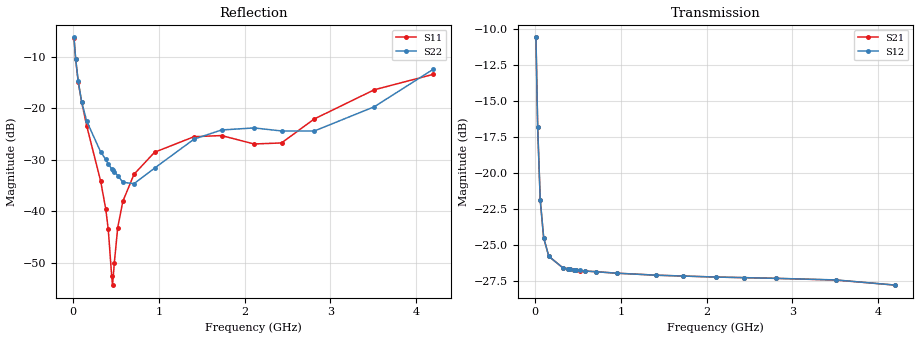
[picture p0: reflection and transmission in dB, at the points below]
! Integrated Device Technology
! Corporate Headquarters
! 6024 Silver Creek Valley Road
! San Jose, CA 95138  USA
! Phone:  1-408-284-8200
! Toll Free:  1-800-223-1366
! Webpage:  http://www.idt.com/
! Timing and RF Division
! 515 Groton Road, Suite 102
! Westford, MA 01886-6024
! Device:  F1950
! Description: 7-bit 0.25 dB Digital Step Attenuator
! Frequency:  150.0 -  4000.00 MHz
! Package:  4x4 mm Thin QFN Plastic Package: 24 pin
! Ports:  2 RF, 12 DC
!  Pin  1  = D0
!  Pin  2  = VDD
!  Pin  3  = Vmode
!  Pin  4  = GND
!  Pin  5  = RF1  =  Port 1
!  Pin  6  = GND
!  Pin  7  = GND
!  Pin  8  = GND
!  Pin  9  = GND
!  Pin 10  = GND
!  Pin 11  = GND
!  Pin 12  = GND
!  Pin 13  = GND
!  Pin 14  = RF2  =  Port 2
!  Pin 15  = GND
!  Pin 16  = LE
!  Pin 17  = CLK
!  Pin 18  = DATE
!  Pin 19  = D6
!  Pin 20  = D5
!  Pin 21  = D4
!  Pin 22  = D3
!  Pin 23  = D2
!  Pin 24  = D1
! State:  104
! Atten State:  26.00 dB
! Voltage:  +5.00 Volts
! Current:  Not Measured mA
! Data:  The device was measured on a the F195X evaluation board which has
!  individual transmission lines to the RF pins.  Data was collected
!  using a calibrated network analyzer.  The evaluation board was
!  de-embedded using a TRL calibration technique.
!  The reference plane is the edge of the package pin.
! Misc:  Board 2019
!  Action Tracker AT0250
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# GHz S dB R 50
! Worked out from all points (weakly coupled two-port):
!   420 points, 10 MHz to 4.2 GHz, reference 50 ohm
!   highest |S21| = -10.60 dB at 10 MHz (marker M1); lowest = -27.8 dB at 4.2 GHz (marker M2)
!   lowest |S11| = -54.3 dB at 460 MHz (marker M3), VSWR 1.00, Z = 49.8 - j0.0947 ohm
!   |S11| at or under -10 dB: 27.19 MHz to end of sweep
!   |S22| runs from -34.9 to -6.3 dB; largest |S21 - S12| = 8.1e-05
!   S11 on the Smith chart (normalised r, x): 10 MHz: 2.03, -1.18; 30 MHz: 1.28, -0.65; 60 MHz: 1.11, -0.37; 380 MHz: 1.01, -0.02; 4.2 GHz: 0.68, +0.17
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0.01  -6.35 -27.6  -10.60 -35.8  -10.60 -35.8  -6.29 -28.7
0.03  -10.55 -50.9  -16.80 -55.2  -16.80 -55.2  -10.49 -52.4
0.06  -14.98 -63.8  -21.89 -50.2  -21.89 -50.2  -14.77 -65.3
0.1  -18.85 -70.5  -24.52 -38.4  -24.52 -38.4  -18.84 -70.9
0.16  -23.52 -72.5  -25.81 -27.6  -25.81 -27.6  -22.57 -76.0
0.32  -34.05 -72.5  -26.59 -17.6  -26.59 -17.6  -28.42 -84.4
0.38  -39.45 -72.6  -26.68 -16.2  -26.67 -16.2  -29.90 -87.1
0.41  -43.48 -80.0  -26.71 -15.7  -26.71 -15.7  -30.77 -88.7
0.45  -52.57 -118.4  -26.75 -15.2  -26.74 -15.2  -31.79 -94.5
0.46  -54.26 -150.6  -26.75 -15.1  -26.75 -15.1  -31.97 -96.2
0.48  -50.05 158.0  -26.77 -15.0  -26.77 -15.0  -32.27 -99.1
0.52  -43.13 142.7  -26.80 -14.7  -26.79 -14.7  -33.05 -102.6
0.58  -38.02 136.6  -26.83 -14.6  -26.83 -14.6  -34.35 -115.1
0.71  -32.80 138.8  -26.88 -14.7  -26.88 -14.7  -34.62 -140.1
0.95  -28.53 146.8  -26.98 -15.8  -26.98 -15.8  -31.60 -176.4
1.41  -25.52 163.3  -27.12 -19.0  -27.12 -19.0  -25.99 160.9
1.73  -25.30 168.6  -27.18 -21.5  -27.18 -21.5  -24.22 152.5
2.11  -26.93 158.4  -27.25 -25.1  -27.25 -25.1  -23.82 142.7
2.43  -26.73 127.1  -27.29 -27.7  -27.29 -27.7  -24.41 132.0
2.81  -22.10 105.9  -27.34 -31.5  -27.34 -31.5  -24.43 116.8
3.51  -16.44 117.8  -27.46 -37.8  -27.45 -37.8  -19.73 113.8
4.2  -13.44 145.8  -27.81 -41.8  -27.81 -41.9  -12.45 127.4
